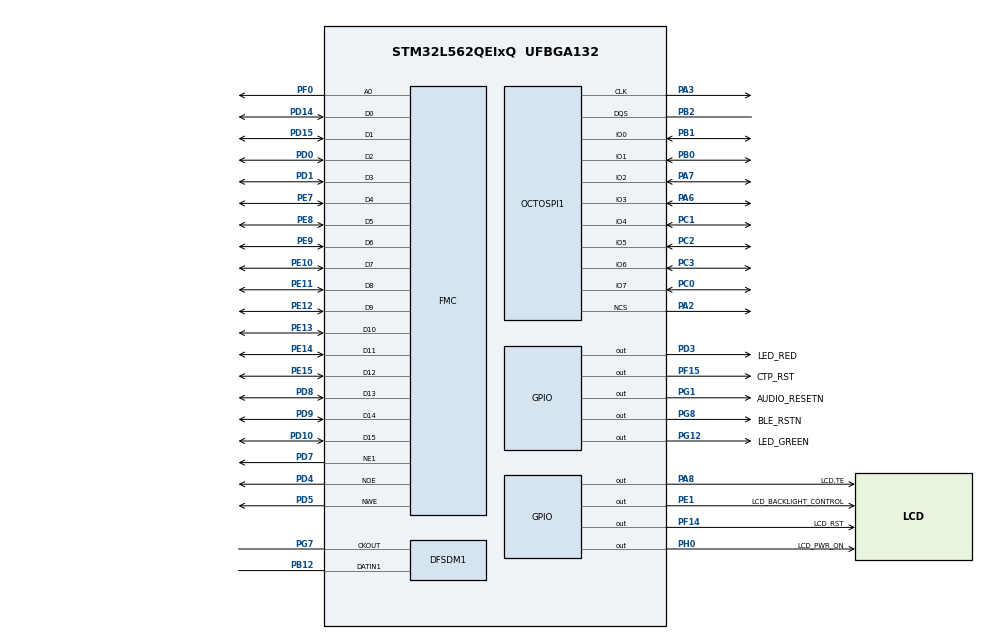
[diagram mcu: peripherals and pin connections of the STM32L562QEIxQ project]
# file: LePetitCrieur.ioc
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RCC.DFSDMCLockSelection=RCC_DFSDM1CLKSOURCE_SYSCLK
PD7.Mode=NorPsramChipSelect1_1
SH.FMC_D7_DA7.1=FMC_D7,16b-d1
SH.FMC_D7_DA7.0=FMC_DA7
RCC.DFSDMAudioCLockSelection=RCC_DFSDM1AUDIOCLKSOURCE_SAI1
SH.FMC_A0.0=FMC_A0,A0_1
PG8.Signal=GPIO_Output
PE1.PinState=GPIO_PIN_RESET
PC15-OSC32_OUT\ (PC15).Mode=LSE-External-Oscillator
SH.FMC_D5_DA5.1=FMC_D5,16b-d1
SH.FMC_D5_DA5.0=FMC_DA5
Dma.DFSDM1_FLT0.0.MemDataAlignment=DMA_MDATAALIGN_WORD
SH.FMC_NWE.0=FMC_NWE,Lcd1
RCC.SYSCLKSource=RCC_SYSCLKSOURCE_PLLCLK
PC14-OSC32_IN\ (PC14).Mode=LSE-External-Oscillator
SH.FMC_D9_DA9.0=FMC_DA9
SH.FMC_D9_DA9.1=FMC_D9,16b-d1
PA14\ (JTCK/SWCLK).Signal=DEBUG_JTCK-SWCLK
Dma.DFSDM1_FLT0.0.Channel_PRIV_NPRIV=DMA_CHANNEL_NPRIV_DISABLE
SH.FMC_D11_DA11.0=FMC_DA11
SH.FMC_D11_DA11.1=FMC_D11,16b-d1
PD4.Signal=FMC_NOE
RCC.APB2TimFreq_Value=110000000
Dma.DFSDM1_FLT0.0.EventEnable=DISABLE
PC3.Signal=OCTOSPI1_IO6
PD0.Signal=FMC_D2_DA2
PD8.Signal=FMC_D13_DA13
PE1.Signal=GPIO_Output
PB2.Signal=OCTOSPI1_DQS
Dma.DFSDM1_FLT0.0.Instance=DMA1_Channel4
PE9.Signal=FMC_D6_DA6
Dma.DFSDM1_FLT0.0.SyncSignalID=NONE
PA8.Signal=GPIO_Output
PA14\ (JTCK/SWCLK).Mode=Trace_Asynchronous_SW
DFSDM1.Fosr_FIL0=64
SH.FMC_D1_DA1.0=FMC_DA1
SH.FMC_D1_DA1.1=FMC_D1,16b-d1
PE10.Signal=FMC_D7_DA7
Mcu.Package=UFBGA132
RCC.SDMMCClockSelection=RCC_SDIOCLKSOURCE_CLK48
PB1.Signal=OCTOSPI1_IO0
PF14.Signal=GPIO_Output
RCC.APB1TimFreq_Value=110000000
NVIC.DMA1_Channel4_IRQn=true\:0\:0\:false\:false\:true\:false\:true
PD15.Signal=FMC_D1_DA1
SH.FMC_D3_DA3.0=FMC_DA3
SH.FMC_D3_DA3.1=FMC_D3,16b-d1
RCC.HSI48_VALUE=48000000
PG12.Signal=GPIO_Output
VP_STMicroelectronics.X-CUBE-TOUCHGFX_VS_GraphicsJjApplication_4.15.0.Mode=GraphicsJjApplication
SH.FMC_D10_DA10.1=FMC_D10,16b-d1
SH.FMC_D10_DA10.0=FMC_DA10
Dma.DFSDM1_FLT0.0.SyncPolarity=HAL_DMAMUX_SYNC_NO_EVENT
PD3.Signal=GPIO_Output
PC2.Signal=OCTOSPI1_IO5
Dma.DFSDM1_FLT0.0.Priority=DMA_PRIORITY_HIGH
PD7.Signal=FMC_NE1
PD1.Signal=FMC_D3_DA3
PF14.GPIO_Label=LCD_RST
PC0.Signal=OCTOSPI1_IO7
SH.FMC_NOE.0=FMC_NOE,Lcd1
Dma.DFSDM1_FLT0.0.SyncEnable=DISABLE
PD10.Signal=FMC_D15_DA15
PA3.Mode=octods_mode
PA8.GPIO_Label=LCD.TE
STMicroelectronics.X-CUBE-TOUCHGFX.4.15.0.ApplicationCcGraphicsJjApplication=TouchGFXOoGenerator
SH.FMC_D15_DA15.1=FMC_D15,16b-d1
SH.FMC_D15_DA15.0=FMC_DA15
VP_ARM.CMSIS_VS_CMSISJjDSP_1.7.0.Mode=CMSISJjDSP
ARM.CMSIS.5.6.0.CMSISJjCORE=true
Dma.DFSDM1_FLT0.0.SignalID=NONE
VP_ARM.CMSIS_VS_CMSISJjCORE_5.3.0.Mode=CMSISJjCORE
PE1.GPIO_Label=LCD_BACKLIGHT_CONTROL
NVIC.DFSDM1_FLT0_IRQn=true\:0\:0\:false\:false\:true\:true\:true
PE14.Signal=FMC_D11_DA11
PE15.Signal=FMC_D12_DA12
PE8.Signal=FMC_D5_DA5
STMicroelectronics.X-CUBE-TOUCHGFX.4.15.0.tgfx_custom_width=240
Mcu.TrustZone=disable
ProjectManager.HeapSize=0x200
PB1.Mode=octods_mode
NVIC.PriorityGroup=NVIC_PRIORITYGROUP_3
DFSDM1.DmaMode_reg_FIL0=ENABLE
PB3\ (JTDO/TRACESWO).Mode=Trace_Asynchronous_SW
DFSDM1.Divider=4
STMicroelectronics.X-CUBE-TOUCHGFX.4.15.0.tgfx_custom_height=240
PB0.Signal=OCTOSPI1_IO1
Dma.DFSDM1_FLT0.0.Polarity=HAL_DMAMUX_REQ_GEN_RISING
PC1.Signal=OCTOSPI1_IO4
PA13\ (JTMS/SWDIO).Signal=DEBUG_JTMS-SWDIO
PC1.Mode=octods_mode
Mcu.Family=STM32L5
PC3.Mode=octods_mode
PA6.Mode=octods_mode
RCC.CortexFreq_Value=110000000
SH.FMC_D14_DA14.0=FMC_DA14
SH.FMC_D14_DA14.1=FMC_D14,16b-d1
PH0-OSC_IN\ (PH0).Signal=GPIO_Output
SH.FMC_D6_DA6.1=FMC_D6,16b-d1
SH.FMC_D6_DA6.0=FMC_DA6
Dma.DFSDM1_FLT0.0.RequestNumber=1
Dma.DFSDM1_FLT0.0.Mode=DMA_CIRCULAR
ProjectManager.StackSize=0x400
DFSDM1.Selection=DFSDM_CHANNEL_OUTPUT_CLOCK_AUDIO
DFSDM1.Oversampling_CH1=10
RCC.HCLKFreq_Value=110000000
RCC.AHBFreq_Value=110000000
RCC.HSE_VALUE=8000000
Dma.DFSDM1_FLT0.0.Direction=DMA_PERIPH_TO_MEMORY
SH.FMC_D8_DA8.0=FMC_DA8
SH.FMC_D8_DA8.1=FMC_D8,16b-d1
DFSDM1.FastMode_reg_FIL0=ENABLE
SH.FMC_D2_DA2.0=FMC_DA2
SH.FMC_D2_DA2.1=FMC_D2,16b-d1
PE13.Signal=FMC_D10_DA10
PA6.Signal=OCTOSPI1_IO3
SH.FMC_D0_DA0.0=FMC_DA0
SH.FMC_D0_DA0.1=FMC_D0,16b-d1
SH.FMC_D4_DA4.1=FMC_D4,16b-d1
SH.FMC_D4_DA4.0=FMC_DA4
VP_PWR_VS_DBSignals.Mode=DisableDeadBatterySignals
PF0.Signal=FMC_A0
PD3.GPIO_Label=LED_RED
RCC.MSIAutoCalibration=ENABLED
RCC.CK48CLockSelection=RCC_USBCLKSOURCE_MSI
PE7.Signal=FMC_D4_DA4
Dma.Request0=DFSDM1_FLT0
SH.S_DATAIN1DFSDM1.0=DFSDM1_DATIN1,PDM_SPI_input_from_ch1_and_internal_clock
DFSDM1.SincOrder_FIL0=DFSDM_FILTER_SINC3_ORDER
Dma.DFSDM1_FLT0.0.SyncRequestNumber=1
RCC.PLLSAI1P=RCC_PLLP_DIV17
RCC.PLLSAI1N=48
PA3.Signal=OCTOSPI1_CLK
RCC.MSI_VALUE=4000000
PG7.Signal=S_CKOUTDFSDM1
PA7.Mode=octods_mode
PA13\ (JTMS/SWDIO).Mode=Trace_Asynchronous_SW
Dma.DFSDM1_FLT0.0.PeriphInc=DMA_PINC_DISABLE
DFSDM1.FilterOrder_CH1=DFSDM_CHANNEL_SINC1_ORDER
PG1.Signal=GPIO_Output
Dma.DFSDM1_FLT0.0.MemInc=DMA_MINC_ENABLE
ARM.CMSIS.5.6.0.CMSISJjDSP=Source
PC2.Mode=octods_mode
PC15-OSC32_OUT\ (PC15).Signal=RCC_OSC32_OUT
PD5.Signal=FMC_NWE
PD9.Signal=FMC_D14_DA14
PC0.Mode=octods_mode
PG8.GPIO_Label=BLE_RSTN
Dma.DFSDM1_FLT0.0.PeriphDataAlignment=DMA_PDATAALIGN_WORD
PB3\ (JTDO/TRACESWO).Signal=DEBUG_JTDO-SWO
ProjectManager.TargetToolchain=STM32CubeIDE
SH.FMC_D13_DA13.0=FMC_DA13
SH.FMC_D13_DA13.1=FMC_D13,16b-d1
RCC.USBFreq_Value=4000000
PE11.Signal=FMC_D8_DA8
PB12.GPIO_Speed=GPIO_SPEED_FREQ_VERY_HIGH
PB0.Mode=octods_mode
board=STM32L562E-DK
RCC.VCOOutputFreq_Value=220000000
PG1.GPIO_Label=AUDIO_RESETN
PG7.GPIO_Speed=GPIO_SPEED_FREQ_VERY_HIGH
RCC.APB2Freq_Value=110000000
SH.S_CKOUTDFSDM1.0=DFSDM1_CKOUT,CKOUT
SH.S_CKOUTDFSDM1.1=DFSDM1_CKOUT,PDM_SPI_input_from_ch1_and_internal_clock
RCC.ADCFreq_Value=96000000
SH.FMC_D12_DA12.1=FMC_D12,16b-d1
SH.FMC_D12_DA12.0=FMC_DA12
PF15.GPIO_Label=CTP_RST
PF15.Signal=GPIO_Output
Mcu.Name=STM32L562QEIxQ
PE12.Signal=FMC_D9_DA9
PA2.Signal=OCTOSPI1_NCS
PD14.Signal=FMC_D0_DA0
RCC.SYSCLKFreq_VALUE=110000000
PC14-OSC32_IN\ (PC14).Signal=RCC_OSC32_IN
PB2.Mode=octods_mode
PG12.GPIO_Label=LED_GREEN
RCC.HSI_VALUE=16000000
PH0-OSC_IN\ (PH0).GPIO_Label=LCD_PWR_ON
RCC.PLLN=55
PA2.Mode=octods_mode
DFSDM1.Filter_regChannel_FIL0=DFSDM_CHANNEL_1
RCC.APB1Freq_Value=110000000
VP_CRC_VS_CRC.Mode=CRC_Activate
PB12.Signal=S_DATAIN1DFSDM1
PA7.Signal=OCTOSPI1_IO2

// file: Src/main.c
/* USER CODE BEGIN Header */
/**
 ******************************************************************************
 * @file           : main.c
 * @brief          : Main program body
 ******************************************************************************
 * @attention
 *
 * <h2><center>&copy; Copyright (c) 2020 STMicroelectronics.
 * All rights reserved.</center></h2>
 *
 * This software component is licensed by ST under BSD 3-Clause license,
 * the "License"; You may not use this file except in compliance with the
 * License. You may obtain a copy of the License at:
 *                        opensource.org/licenses/BSD-3-Clause
 *
 ******************************************************************************
 */
/* USER CODE END Header */

#include "main.h"

#include "crc.h"
#include "dfsdm.h"
#include "dma.h"
#include "fmc.h"
#include "gpio.h"
#include "octospi.h"

/* USER CODE BEGIN Includes */
#include <stdbool.h>
#include <stdio.h>
#include <stdlib.h>

#include "stm32_lcd.h"
#include "stm32l562e_discovery_lcd.h"
/* USER CODE END Includes */

/* USER CODE BEGIN PD */
#define RECORD_BUFFER_SIZE 2048  //!< Maximum number of samples for FFT is 1024
#define NUMBER_BUFFER_SAVE \
  323  //!< We want to save 15s of sound after first detection of high noise.
       //!< We're sampling at 44.1kHz, which thus requires 661500 samples, or
       //!< 323 buffers of 2048 samples.

/* USER CODE END PD */

/* USER CODE BEGIN PV */
extern DFSDM_Filter_HandleTypeDef hdfsdm1_filter0;
int32_t record_buffer[RECORD_BUFFER_SIZE];
__IO uint32_t DmaRecHalfBuffCplt = 0;
__IO uint32_t DmaRecBuffCplt = 0;
uint16_t number_half_buffer_saved;
bool flag_save_buffer = false;
bool flag_display_lcd_info = false;
/* USER CODE END PV */

void SystemClock_Config(void);
/* USER CODE BEGIN PFP */
void LCD_Init(void);
void LCD_DeInit(void);
void LCD_Display_Microphone_Info_Init(void);
void LCD_Display_Microphone_Info_Update(uint32_t i_extreme_detected,
                                        uint32_t i_tick_begin);
void turn_off_user_leds(void);
void enter_low_power_mode(void);
void exit_low_power_mode(void);
void change_system_clock_to_low_power(void);

/* USER CODE END PFP */

int main(void) {

  /* MCU
   * Configuration--------------------------------------------------------*/

  /* Reset of all peripherals, Initializes the Flash interface and the
   * Systick.
   */
  HAL_Init();

  /* Configure the system clock */
  SystemClock_Config();

  /* Initialize all configured peripherals */
  MX_GPIO_Init();
  MX_DMA_Init();
  MX_DFSDM1_Init(DFSDM_NORMAL_MODE);
  DFSDM_activate_analog_watchdog(1000, DFSDM_ANALOG_WATCHDOG_MIN_THRESHOLD);
  MX_FMC_Init();
  /* USER CODE BEGIN 2 */

  LCD_DeInit();
  // Start DFSDM conversions
  if (HAL_OK != HAL_DFSDM_FilterRegularStart_DMA(
                    &hdfsdm1_filter0, record_buffer, RECORD_BUFFER_SIZE)) {
    Error_Handler();
  }
  /* USER CODE END 2 */

  /* Infinite loop */
  /* USER CODE BEGIN WHILE */
  while (1) {
    if (DmaRecHalfBuffCplt == 1 || DmaRecBuffCplt == 1) {
      uint16_t i_start_save_buffer = 0;
      if (DmaRecBuffCplt == 1) {
        i_start_save_buffer = 0;
        DmaRecBuffCplt = 0;
      } else {
        i_start_save_buffer = RECORD_BUFFER_SIZE / 2;
        DmaRecHalfBuffCplt = 0;
      }

      // Perform actions when it's required to save the record buffers
      if (flag_save_buffer == true) {
        // save buffer
        HAL_GPIO_TogglePin(LED_GREEN_GPIO_Port, LED_GREEN_Pin);
        number_half_buffer_saved++;
        if (number_half_buffer_saved == 2 * NUMBER_BUFFER_SAVE) {
          flag_save_buffer = false;
        }
      }

      // If the display is no longer needed, turn it off
      if (flag_display_lcd_info == false) {
        LCD_DeInit();
      }

      // If there's no action currently performed, go back to sleep
      if (flag_save_buffer == false && flag_display_lcd_info == false) {
        enter_low_power_mode();
        // System will be waken up by interrupt
        exit_low_power_mode();
      }
    }
    /* USER CODE END WHILE */

  }
}

void SystemClock_Config(void) {
  RCC_OscInitTypeDef RCC_OscInitStruct = {0};
  RCC_ClkInitTypeDef RCC_ClkInitStruct = {0};

  // Configure the system clock to not use the PLL to be able to configure it
  // just after
  RCC_OscInitStruct.OscillatorType = RCC_OSCILLATORTYPE_MSI;
  RCC_OscInitStruct.MSIState = RCC_MSI_ON;
  RCC_OscInitStruct.MSICalibrationValue = RCC_MSICALIBRATION_DEFAULT;
  RCC_OscInitStruct.MSIClockRange = RCC_MSIRANGE_6;
  RCC_OscInitStruct.PLL.PLLState = RCC_PLL_NONE;
  if (HAL_RCC_OscConfig(&RCC_OscInitStruct) != HAL_OK) {
    Error_Handler();
  }
  RCC_ClkInitStruct.ClockType = RCC_CLOCKTYPE_SYSCLK;
  RCC_ClkInitStruct.SYSCLKSource = RCC_SYSCLKSOURCE_MSI;
  if (HAL_RCC_ClockConfig(&RCC_ClkInitStruct, FLASH_LATENCY_5) != HAL_OK) {
    Error_Handler();
  }

  /** Configure the main internal regulator output voltage
   */
  if (HAL_PWREx_ControlVoltageScaling(PWR_REGULATOR_VOLTAGE_SCALE0) != HAL_OK) {
    Error_Handler();
  }
  /** Configure LSE Drive Capability
   */
  HAL_PWR_EnableBkUpAccess();
  __HAL_RCC_LSEDRIVE_CONFIG(RCC_LSEDRIVE_LOW);
  /** Initializes the RCC Oscillators according to the specified parameters
   * in the RCC_OscInitTypeDef structure.
   */
  RCC_OscInitStruct.OscillatorType =
      RCC_OSCILLATORTYPE_LSE | RCC_OSCILLATORTYPE_MSI;
  RCC_OscInitStruct.LSEState = RCC_LSE_ON;
  RCC_OscInitStruct.MSIState = RCC_MSI_ON;
  RCC_OscInitStruct.MSICalibrationValue = RCC_MSICALIBRATION_DEFAULT;
  RCC_OscInitStruct.MSIClockRange = RCC_MSIRANGE_6;
  RCC_OscInitStruct.PLL.PLLState = RCC_PLL_ON;
  RCC_OscInitStruct.PLL.PLLSource = RCC_PLLSOURCE_MSI;
  RCC_OscInitStruct.PLL.PLLM = 1;
  RCC_OscInitStruct.PLL.PLLN = 55;
  RCC_OscInitStruct.PLL.PLLP = RCC_PLLP_DIV7;
  RCC_OscInitStruct.PLL.PLLQ = RCC_PLLQ_DIV2;
  RCC_OscInitStruct.PLL.PLLR = RCC_PLLR_DIV2;
  if (HAL_RCC_OscConfig(&RCC_OscInitStruct) != HAL_OK) {
    Error_Handler();
  }
  /** Initializes the CPU, AHB and APB buses clocks
   */
  RCC_ClkInitStruct.ClockType = RCC_CLOCKTYPE_HCLK | RCC_CLOCKTYPE_SYSCLK |
                                RCC_CLOCKTYPE_PCLK1 | RCC_CLOCKTYPE_PCLK2;
  RCC_ClkInitStruct.SYSCLKSource = RCC_SYSCLKSOURCE_PLLCLK;
  RCC_ClkInitStruct.AHBCLKDivider = RCC_SYSCLK_DIV1;
  RCC_ClkInitStruct.APB1CLKDivider = RCC_HCLK_DIV1;
  RCC_ClkInitStruct.APB2CLKDivider = RCC_HCLK_DIV1;

  if (HAL_RCC_ClockConfig(&RCC_ClkInitStruct, FLASH_LATENCY_5) != HAL_OK) {
    Error_Handler();
  }
  /** Enable MSI Auto calibration
   */
  HAL_RCCEx_EnableMSIPLLMode();
}

/* USER CODE BEGIN 4 */

void LCD_Init(void) {
  LCD_UTILS_Drv_t lcdDrv;

  /* Initialize the LCD */
  if (BSP_LCD_Init(0, LCD_ORIENTATION_PORTRAIT) != BSP_ERROR_NONE) {
    Error_Handler();
  }

  /* Set UTIL_LCD functions */
  lcdDrv.DrawBitmap = BSP_LCD_DrawBitmap;
  lcdDrv.FillRGBRect = BSP_LCD_FillRGBRect;
  lcdDrv.DrawHLine = BSP_LCD_DrawHLine;
  lcdDrv.DrawVLine = BSP_LCD_DrawVLine;
  lcdDrv.FillRect = BSP_LCD_FillRect;
  lcdDrv.GetPixel = BSP_LCD_ReadPixel;
  lcdDrv.SetPixel = BSP_LCD_WritePixel;
  lcdDrv.GetXSize = BSP_LCD_GetXSize;
  lcdDrv.GetYSize = BSP_LCD_GetYSize;
  lcdDrv.SetLayer = BSP_LCD_SetActiveLayer;
  lcdDrv.GetFormat = BSP_LCD_GetFormat;
  UTIL_LCD_SetFuncDriver(&lcdDrv);

  /* Clear the LCD */
  UTIL_LCD_Clear(UTIL_LCD_COLOR_WHITE);

  /* Set the display on */
  if (BSP_LCD_DisplayOn(0) != BSP_ERROR_NONE) {
    Error_Handler();
  }
}

void LCD_DeInit(void) {
  /* Deinitialize the LCD */
  if (BSP_LCD_DeInit(0) != BSP_ERROR_NONE) {
    Error_Handler();
  }
}

void turn_off_user_leds(void) {
  HAL_GPIO_WritePin(LED_RED_GPIO_Port, LED_RED_Pin, GPIO_PIN_SET);
  HAL_GPIO_WritePin(LED_GREEN_GPIO_Port, LED_GREEN_Pin, GPIO_PIN_SET);
}

/**
 * \brief Change the clocks configuration for a low energy consumption
 *
 * Begin by making sure that the MSI is running at 4MHz (range 6). When this is
 * done, set the SYS clock to use the MSI. This value is chosen to be high
 * enough for the DSFDM to be able to perform properly (the rate of samples of
 * the microphone is 11.3MHz (SAI1 clock) / 16 (DFSDM output clock divider) =
 * 706kHz, and the clock of the DFSDM must be at least 4 times this value).
 *
 * At this point, the PLL isn't used anymore so disable it, then change the
 * voltage scaling to the range 2 which can only go up to 26MHz (which explains
 * why we change the frequency first) but is more energy efficient.
 *
 * Disable the MSI auto-calibration feature that won't be needed, and disable
 * the LSE that was on only for this auto-calibration.
 *
 * Finish by setting a prescaler for AHB clock of 16, which decreases the
 * different system clocks to 250kHz.
 *
 */
void change_system_clock_to_low_power(void) {
  RCC_ClkInitTypeDef RCC_ClkInitStruct = {0};
  RCC_OscInitTypeDef RCC_OscInitStruct = {0};

  // Configure the system clock to use the MSI clock instead of the clock coming
  // from the PLL, which becomes unused.
  RCC_OscInitStruct.OscillatorType = RCC_OSCILLATORTYPE_MSI;
  RCC_OscInitStruct.MSIState = RCC_MSI_ON;
  RCC_OscInitStruct.MSICalibrationValue = RCC_MSICALIBRATION_DEFAULT;
  RCC_OscInitStruct.MSIClockRange = RCC_MSIRANGE_6;
  RCC_OscInitStruct.PLL.PLLState = RCC_PLL_NONE;
  if (HAL_RCC_OscConfig(&RCC_OscInitStruct) != HAL_OK) {
    Error_Handler();
  }
  RCC_ClkInitStruct.ClockType = RCC_CLOCKTYPE_SYSCLK;
  RCC_ClkInitStruct.SYSCLKSource = RCC_SYSCLKSOURCE_MSI;
  if (HAL_RCC_ClockConfig(&RCC_ClkInitStruct, FLASH_LATENCY_5) != HAL_OK) {
    Error_Handler();
  }

  // Turn off the PLL now that the SYS clock source has been changed
  RCC_OscInitStruct.OscillatorType = RCC_OSCILLATORTYPE_NONE;
  RCC_OscInitStruct.PLL.PLLState = RCC_PLL_OFF;
  if (HAL_RCC_OscConfig(&RCC_OscInitStruct) != HAL_OK) {
    Error_Handler();
  }

  // Configure the main internal regulator output voltage
  if (HAL_PWREx_ControlVoltageScaling(PWR_REGULATOR_VOLTAGE_SCALE2) != HAL_OK) {
    Error_Handler();
  }

  // Disable MSI auto-calibration not needed for analog watchdog and disable the
  // LSE, only used for the auto-calibration
  HAL_RCCEx_DisableMSIPLLMode();
  RCC_OscInitStruct.OscillatorType = RCC_OSCILLATORTYPE_LSE;
  RCC_OscInitStruct.LSEState =
      RCC_LSE_OFF;  // could also be changed to RTC only if needed
  RCC_OscInitStruct.PLL.PLLState = RCC_PLL_NONE;
  if (HAL_RCC_OscConfig(&RCC_OscInitStruct) != HAL_OK) {
    Error_Handler();
  }

  // Apply an additionnal divider (16) in the clock tree to obtain a HCLK of
  // 250kHz
  RCC_ClkInitStruct.ClockType = RCC_CLOCKTYPE_HCLK;
  RCC_ClkInitStruct.AHBCLKDivider = RCC_SYSCLK_DIV16;
  if (HAL_RCC_ClockConfig(&RCC_ClkInitStruct, FLASH_LATENCY_5) != HAL_OK) {
    Error_Handler();
  }
}

void enter_low_power_mode(void) {
  turn_off_user_leds();
  HAL_DFSDM_FilterRegularStop_DMA(&hdfsdm1_filter0);
  MX_DMA_DeInit();
  MX_FMC_DeInit();
  MX_OCTOSPI1_DeInit();
  MX_CRC_DeInit();
  change_system_clock_to_low_power();
  HAL_SuspendTick();
  MX_DFSDM1_Init(DFSDM_LOW_POWER_MODE);
  DFSDM_activate_analog_watchdog(1000, DFSDM_ANALOG_WATCHDOG_MIN_THRESHOLD);
  HAL_PWR_EnterSLEEPMode(PWR_MAINREGULATOR_ON, PWR_SLEEPENTRY_WFI);
}

void exit_low_power_mode(void) {
  DFSDM_deactivate_analog_watchdog();
  SystemClock_Config();
  HAL_ResumeTick();
  MX_FMC_Init();
  MX_DMA_Init();
  MX_DFSDM1_Init(DFSDM_NORMAL_MODE);
  HAL_DFSDM_FilterRegularStart_DMA(&hdfsdm1_filter0, record_buffer,
                                   RECORD_BUFFER_SIZE);
  MX_OCTOSPI1_Init();
  MX_CRC_Init();
}

/**
 * @brief  Half regular conversion complete callback.
 * @param  hdfsdm_filter : DFSDM filter handle.
 * @retval None
 */
void HAL_DFSDM_FilterRegConvHalfCpltCallback(
    DFSDM_Filter_HandleTypeDef *hdfsdm_filter) {
  if (hdfsdm_filter == &hdfsdm1_filter0) {
    DmaRecHalfBuffCplt = 1;
  }
}

void LCD_Display_Microphone_Info_Init(void) {
  UTIL_LCD_SetFont(&Font12);

  /* Set the LCD Text Color */
  UTIL_LCD_SetTextColor(UTIL_LCD_COLOR_DARKBLUE);
  UTIL_LCD_SetBackColor(UTIL_LCD_COLOR_WHITE);

  /* Display LCD messages */
  UTIL_LCD_DisplayStringAt(0, 10, (uint8_t *)"Max detected", LEFT_MODE);
  UTIL_LCD_DrawHLine(0, 30, 240, UTIL_LCD_COLOR_DARKBLUE);
  UTIL_LCD_DisplayStringAt(0, 35, (uint8_t *)"Time", LEFT_MODE);
}

void LCD_Display_Microphone_Info_Update(uint32_t i_extreme_detected,
                                        uint32_t i_tick_begin) {
  char message_detected[64] = {'\0'}, message_time[64] = {'\0'};
  sprintf(message_detected, "%010lu", i_extreme_detected);

  UTIL_LCD_SetFont(&Font12);

  /* Set the LCD Text Color */
  UTIL_LCD_SetTextColor(UTIL_LCD_COLOR_DARKBLUE);
  UTIL_LCD_SetBackColor(UTIL_LCD_COLOR_WHITE);

  /* Display LCD messages */
  UTIL_LCD_DisplayStringAt(0, 10, (uint8_t *)message_detected, RIGHT_MODE);
  sprintf(message_time, "%03lu", HAL_GetTick() - i_tick_begin);
  UTIL_LCD_DisplayStringAt(0, 35, (uint8_t *)message_time, RIGHT_MODE);
}

/**
  * @brief  Regular conversion complete callback.
  * @note   In interrupt mode, user has to read conversion value in this
  function using HAL_DFSDM_FilterGetRegularValue.
  * @param  hdfsdm_filter : DFSDM filter handle.
  * @retval None
  */
void HAL_DFSDM_FilterRegConvCpltCallback(
    DFSDM_Filter_HandleTypeDef *hdfsdm_filter) {
  if (hdfsdm_filter == &hdfsdm1_filter0) {
    DmaRecBuffCplt = 1;
  }
}

/**
 * @brief  Filter analog watchdog callback.
 * @param  hdfsdm_filter DFSDM filter handle.
 * @param  Channel Corresponding channel.
 * @param  Threshold Low or high threshold has been reached.
 * @retval None
 */
void HAL_DFSDM_FilterAwdCallback(DFSDM_Filter_HandleTypeDef *hdfsdm_filter,
                                 uint32_t Channel, uint32_t Threshold) {
  if (hdfsdm_filter == &hdfsdm1_filter0 && Channel == 1 &&
      flag_save_buffer == false) {
    flag_save_buffer = true;
    number_half_buffer_saved = 0;
  }
}

/* USER CODE END 4 */

void Error_Handler(void) {
  /* USER CODE BEGIN Error_Handler_Debug */
  /* User can add his own implementation to report the HAL error return state
   */
  while (1) {
    /* Toggle LED_RED with a period of one second */
    HAL_GPIO_TogglePin(LED_RED_GPIO_Port, LED_RED_Pin);
    HAL_Delay(1000);
  }
  /* USER CODE END Error_Handler_Debug */
}

#ifdef USE_FULL_ASSERT
/**
 * @brief  Reports the name of the source file and the source line number
 *         where the assert_param error has occurred.
 * @param  file: pointer to the source file name
 * @param  line: assert_param error line source number
 * @retval None
 */
void assert_failed(uint8_t *file, uint32_t line) {
  /* USER CODE BEGIN 6 */
  /* User can add his own implementation to report the file name and line
     number,
     tex: printf("Wrong parameters value: file %s on line %d\r\n", file, line)
   */
  /* USER CODE END 6 */
}
#endif /* USE_FULL_ASSERT */

/************************ (C) COPYRIGHT STMicroelectronics *****END OF
 * FILE****/
